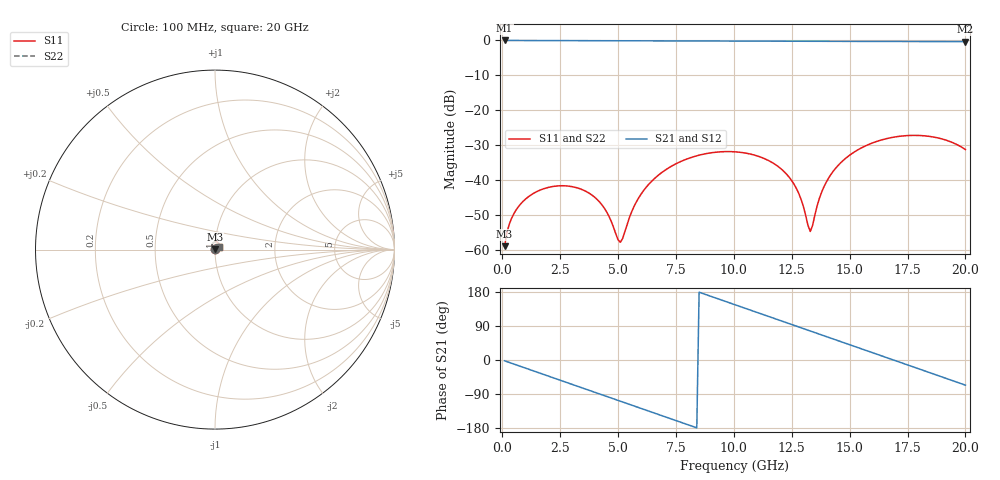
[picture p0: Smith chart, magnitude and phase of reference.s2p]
! circuitRF F0 spike reference -- case B, Palace, copper voids with conductivity boundary, tand 0.004
! Palace postpro/port-S.csv, dB/deg -> RI; port 1 excited only; S22 = S11 and S12 = S21 by the 180-degree rotational symmetry of the geometry
# GHz S RI R 50
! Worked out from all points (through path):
!   200 points, 100 MHz to 20 GHz, reference 50 ohm
!   highest |S21| = -0.01 dB at 100 MHz (marker M1); lowest = -0.3 dB at 20 GHz (marker M2)
!   group delay of S21, straight-line fit = 59.2 ps
!   lowest |S11| = -58.9 dB at 100 MHz (marker M3), VSWR 1.00, Z = 50.1 + j0.0972 ohm
!   |S11| at or under -10 dB: start of sweep to end of sweep
!   |S22| runs from -58.9 to -27.2 dB; largest |S21 - S12| = 0
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0.1  0.000592 0.000971  0.9986 -0.0378  0.9986 -0.0378  0.000592 0.000971
0.3  0.00116 0.00203  0.9924 -0.1122  0.9924 -0.1122  0.00116 0.00203
0.5  0.00171 0.00284  0.9808 -0.1857  0.9808 -0.1857  0.00171 0.00284
1.2  0.00394 0.00456  0.8985 -0.4317  0.8985 -0.4317  0.00394 0.00456
2.3  0.00724 0.00393  0.6513 -0.752  0.6513 -0.752  0.00724 0.00393
3.5  0.00721 0.000246  0.2624 -0.9574  0.2624 -0.9574  0.00721 0.000246
4.4  0.00362 -0.00172  -0.0665 -0.9889  -0.0665 -0.9889  0.00362 -0.00172
5.1  -0.000543 -0.00117  -0.3182 -0.9372  -0.3182 -0.9372  -0.000543 -0.00117
5.8  -0.00463 0.00178  -0.5479 -0.8226  -0.5479 -0.8226  -0.00463 0.00178
6.8  -0.00765 0.00956  -0.8074 -0.5662  -0.8074 -0.5662  -0.00765 0.00956
8.4  -0.00066 0.0223  -0.9824 -0.0169  -0.9824 -0.0169  -0.00066 0.0223
10.1  0.0149 0.0206  -0.8 0.5638  -0.8 0.5638  0.0149 0.0206
12.2  0.0129 0.0011  -0.1715 0.9595  -0.1715 0.9595  0.0129 0.0011
12.8  0.00624 -0.00182  0.0449 0.9726  0.0449 0.9726  0.00624 -0.00182
13.3  -0.000308 -0.00182  0.2238 0.9467  0.2238 0.9467  -0.000308 -0.00182
13.4  -0.00164 -0.00153  0.2588 0.9375  0.2588 0.9375  -0.00164 -0.00153
13.8  -0.00683 0.000641  0.3947 0.8881  0.3947 0.8881  -0.00683 0.000641
14.4  -0.0133 0.00665  0.5809 0.7778  0.5809 0.7778  -0.0133 0.00665
15.4  -0.0175 0.0215  0.8224 0.5122  0.8224 0.5122  -0.0175 0.0215
16.7  -0.00749 0.0394  0.9638 0.0704  0.9638 0.0704  -0.00749 0.0394
18.3  0.0162 0.0398  0.8348 -0.4817  0.8348 -0.4817  0.0162 0.0398
20  0.0217 0.0169  0.3857 -0.8812  0.3857 -0.8812  0.0217 0.0169
